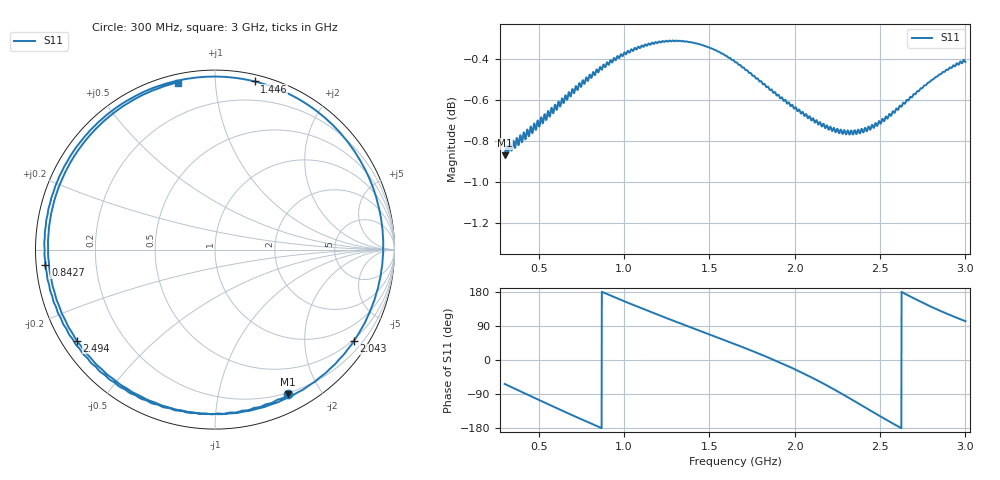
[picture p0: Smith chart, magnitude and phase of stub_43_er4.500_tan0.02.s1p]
! Chirptenna · simulación 3D de un stub abierto
# HZ S RI R 50
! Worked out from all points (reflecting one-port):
!   2001 points, 300 MHz to 3 GHz, reference 50 ohm
!   lowest |S11| = -0.9 dB at 300 MHz (marker M1), VSWR 19.97, Z = 9.07 - j80.6 ohm
!   phase of S11 starts at -63 deg and turns -554 deg over the sweep
!   S11 on the Smith chart (normalised r, x): 300 MHz: 0.18, -1.61; 842.7 MHz: 0.03, -0.05; 1.446 GHz: 0.05, +1.26; 2.043 GHz: 0.45, -3.27; 2.494 GHz: 0.04, -0.30; 3 GHz: 0.04, +0.80
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3e8  0.4083 -0.8072
3.8235e8  0.1508 -0.8974
4.6335e8  -0.1192 -0.9082
5.4435e8  -0.381 -0.8404
6.375e8  -0.6447 -0.6757
7.4685e8  -0.8574 -0.3852
8.427e8  -0.945 -0.0859
9.75e8  -0.898 0.3277
1.15455e9  -0.5807 0.7675
1.3125e9  -0.1593 0.9512
1.44615e9  0.2213 0.9368
1.54605e9  0.4839 0.8279
1.65e9  0.7108 0.635
1.8309e9  0.9281 0.1504
1.91325e9  0.928 -0.108
1.9875e9  0.8643 -0.3445
2.04285e9  0.7728 -0.5114
2.1981e9  0.3199 -0.8603
2.26155e9  0.0724 -0.9132
2.325e9  -0.1884 -0.8964
2.40195e9  -0.4897 -0.7745
2.49375e9  -0.7701 -0.5073
2.58015e9  -0.9096 -0.178
2.6625e9  -0.9213 0.1468
2.7435e9  -0.8327 0.4346
2.8353e9  -0.6463 0.6901
2.919e9  -0.4307 0.8467
3e9  -0.2062 0.9306
